# Generated by FakeRAM 2.0
VERSION 5.7 ;
BUSBITCHARS "[]" ;
PROPERTYDEFINITIONS
  MACRO width INTEGER ;
  MACRO depth INTEGER ;
  MACRO banks INTEGER ;
END PROPERTYDEFINITIONS
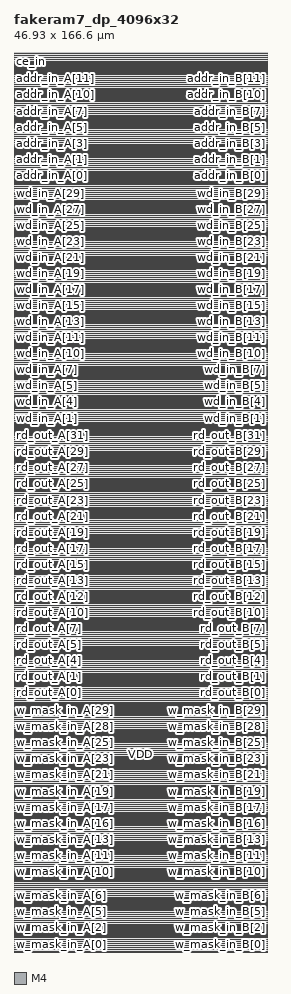
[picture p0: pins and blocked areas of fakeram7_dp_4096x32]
MACRO fakeram7_dp_4096x32
  PROPERTY width 32 ;
  PROPERTY depth 4096 ;
  PROPERTY banks 8 ;
  FOREIGN fakeram7_dp_4096x32 0 0 ;
  SYMMETRY X Y ;
  SIZE 46.930 BY 166.600 ;
  CLASS BLOCK ;
  PIN w_mask_in_A[0]
    DIRECTION INPUT ;
    USE SIGNAL ;
    SHAPE ABUTMENT ;
    PORT
      LAYER M4 ;
      RECT 0.000 0.048 0.024 0.072 ;
    END
  END w_mask_in_A[0]
  PIN w_mask_in_B[0]
    DIRECTION INPUT ;
    USE SIGNAL ;
    SHAPE ABUTMENT ;
    PORT
      LAYER M4 ;
      RECT 46.906 0.048 46.930 0.072 ;
    END
  END w_mask_in_B[0]
  PIN w_mask_in_A[1]
    DIRECTION INPUT ;
    USE SIGNAL ;
    SHAPE ABUTMENT ;
    PORT
      LAYER M4 ;
      RECT 0.000 1.536 0.024 1.560 ;
    END
  END w_mask_in_A[1]
  PIN w_mask_in_B[1]
    DIRECTION INPUT ;
    USE SIGNAL ;
    SHAPE ABUTMENT ;
    PORT
      LAYER M4 ;
      RECT 46.906 1.536 46.930 1.560 ;
    END
  END w_mask_in_B[1]
  PIN w_mask_in_A[2]
    DIRECTION INPUT ;
    USE SIGNAL ;
    SHAPE ABUTMENT ;
    PORT
      LAYER M4 ;
      RECT 0.000 3.024 0.024 3.048 ;
    END
  END w_mask_in_A[2]
  PIN w_mask_in_B[2]
    DIRECTION INPUT ;
    USE SIGNAL ;
    SHAPE ABUTMENT ;
    PORT
      LAYER M4 ;
      RECT 46.906 3.024 46.930 3.048 ;
    END
  END w_mask_in_B[2]
  PIN w_mask_in_A[3]
    DIRECTION INPUT ;
    USE SIGNAL ;
    SHAPE ABUTMENT ;
    PORT
      LAYER M4 ;
      RECT 0.000 4.512 0.024 4.536 ;
    END
  END w_mask_in_A[3]
  PIN w_mask_in_B[3]
    DIRECTION INPUT ;
    USE SIGNAL ;
    SHAPE ABUTMENT ;
    PORT
      LAYER M4 ;
      RECT 46.906 4.512 46.930 4.536 ;
    END
  END w_mask_in_B[3]
  PIN w_mask_in_A[4]
    DIRECTION INPUT ;
    USE SIGNAL ;
    SHAPE ABUTMENT ;
    PORT
      LAYER M4 ;
      RECT 0.000 6.000 0.024 6.024 ;
    END
  END w_mask_in_A[4]
  PIN w_mask_in_B[4]
    DIRECTION INPUT ;
    USE SIGNAL ;
    SHAPE ABUTMENT ;
    PORT
      LAYER M4 ;
      RECT 46.906 6.000 46.930 6.024 ;
    END
  END w_mask_in_B[4]
  PIN w_mask_in_A[5]
    DIRECTION INPUT ;
    USE SIGNAL ;
    SHAPE ABUTMENT ;
    PORT
      LAYER M4 ;
      RECT 0.000 7.488 0.024 7.512 ;
    END
  END w_mask_in_A[5]
  PIN w_mask_in_B[5]
    DIRECTION INPUT ;
    USE SIGNAL ;
    SHAPE ABUTMENT ;
    PORT
      LAYER M4 ;
      RECT 46.906 7.488 46.930 7.512 ;
    END
  END w_mask_in_B[5]
  PIN w_mask_in_A[6]
    DIRECTION INPUT ;
    USE SIGNAL ;
    SHAPE ABUTMENT ;
    PORT
      LAYER M4 ;
      RECT 0.000 8.976 0.024 9.000 ;
    END
  END w_mask_in_A[6]
  PIN w_mask_in_B[6]
    DIRECTION INPUT ;
    USE SIGNAL ;
    SHAPE ABUTMENT ;
    PORT
      LAYER M4 ;
      RECT 46.906 8.976 46.930 9.000 ;
    END
  END w_mask_in_B[6]
  PIN w_mask_in_A[7]
    DIRECTION INPUT ;
    USE SIGNAL ;
    SHAPE ABUTMENT ;
    PORT
      LAYER M4 ;
      RECT 0.000 10.464 0.024 10.488 ;
    END
  END w_mask_in_A[7]
  PIN w_mask_in_B[7]
    DIRECTION INPUT ;
    USE SIGNAL ;
    SHAPE ABUTMENT ;
    PORT
      LAYER M4 ;
      RECT 46.906 10.464 46.930 10.488 ;
    END
  END w_mask_in_B[7]
  PIN w_mask_in_A[8]
    DIRECTION INPUT ;
    USE SIGNAL ;
    SHAPE ABUTMENT ;
    PORT
      LAYER M4 ;
      RECT 0.000 11.952 0.024 11.976 ;
    END
  END w_mask_in_A[8]
  PIN w_mask_in_B[8]
    DIRECTION INPUT ;
    USE SIGNAL ;
    SHAPE ABUTMENT ;
    PORT
      LAYER M4 ;
      RECT 46.906 11.952 46.930 11.976 ;
    END
  END w_mask_in_B[8]
  PIN w_mask_in_A[9]
    DIRECTION INPUT ;
    USE SIGNAL ;
    SHAPE ABUTMENT ;
    PORT
      LAYER M4 ;
      RECT 0.000 13.440 0.024 13.464 ;
    END
  END w_mask_in_A[9]
  PIN w_mask_in_B[9]
    DIRECTION INPUT ;
    USE SIGNAL ;
    SHAPE ABUTMENT ;
    PORT
      LAYER M4 ;
      RECT 46.906 13.440 46.930 13.464 ;
    END
  END w_mask_in_B[9]
  PIN w_mask_in_A[10]
    DIRECTION INPUT ;
    USE SIGNAL ;
    SHAPE ABUTMENT ;
    PORT
      LAYER M4 ;
      RECT 0.000 14.928 0.024 14.952 ;
    END
  END w_mask_in_A[10]
  PIN w_mask_in_B[10]
    DIRECTION INPUT ;
    USE SIGNAL ;
    SHAPE ABUTMENT ;
    PORT
      LAYER M4 ;
      RECT 46.906 14.928 46.930 14.952 ;
    END
  END w_mask_in_B[10]
  PIN w_mask_in_A[11]
    DIRECTION INPUT ;
    USE SIGNAL ;
    SHAPE ABUTMENT ;
    PORT
      LAYER M4 ;
      RECT 0.000 16.416 0.024 16.440 ;
    END
  END w_mask_in_A[11]
  PIN w_mask_in_B[11]
    DIRECTION INPUT ;
    USE SIGNAL ;
    SHAPE ABUTMENT ;
    PORT
      LAYER M4 ;
      RECT 46.906 16.416 46.930 16.440 ;
    END
  END w_mask_in_B[11]
  PIN w_mask_in_A[12]
    DIRECTION INPUT ;
    USE SIGNAL ;
    SHAPE ABUTMENT ;
    PORT
      LAYER M4 ;
      RECT 0.000 17.904 0.024 17.928 ;
    END
  END w_mask_in_A[12]
  PIN w_mask_in_B[12]
    DIRECTION INPUT ;
    USE SIGNAL ;
    SHAPE ABUTMENT ;
    PORT
      LAYER M4 ;
      RECT 46.906 17.904 46.930 17.928 ;
    END
  END w_mask_in_B[12]
  PIN w_mask_in_A[13]
    DIRECTION INPUT ;
    USE SIGNAL ;
    SHAPE ABUTMENT ;
    PORT
      LAYER M4 ;
      RECT 0.000 19.392 0.024 19.416 ;
    END
  END w_mask_in_A[13]
  PIN w_mask_in_B[13]
    DIRECTION INPUT ;
    USE SIGNAL ;
    SHAPE ABUTMENT ;
    PORT
      LAYER M4 ;
      RECT 46.906 19.392 46.930 19.416 ;
    END
  END w_mask_in_B[13]
  PIN w_mask_in_A[14]
    DIRECTION INPUT ;
    USE SIGNAL ;
    SHAPE ABUTMENT ;
    PORT
      LAYER M4 ;
      RECT 0.000 20.880 0.024 20.904 ;
    END
  END w_mask_in_A[14]
  PIN w_mask_in_B[14]
    DIRECTION INPUT ;
    USE SIGNAL ;
    SHAPE ABUTMENT ;
    PORT
      LAYER M4 ;
      RECT 46.906 20.880 46.930 20.904 ;
    END
  END w_mask_in_B[14]
  PIN w_mask_in_A[15]
    DIRECTION INPUT ;
    USE SIGNAL ;
    SHAPE ABUTMENT ;
    PORT
      LAYER M4 ;
      RECT 0.000 22.368 0.024 22.392 ;
    END
  END w_mask_in_A[15]
  PIN w_mask_in_B[15]
    DIRECTION INPUT ;
    USE SIGNAL ;
    SHAPE ABUTMENT ;
    PORT
      LAYER M4 ;
      RECT 46.906 22.368 46.930 22.392 ;
    END
  END w_mask_in_B[15]
  PIN w_mask_in_A[16]
    DIRECTION INPUT ;
    USE SIGNAL ;
    SHAPE ABUTMENT ;
    PORT
      LAYER M4 ;
      RECT 0.000 23.856 0.024 23.880 ;
    END
  END w_mask_in_A[16]
  PIN w_mask_in_B[16]
    DIRECTION INPUT ;
    USE SIGNAL ;
    SHAPE ABUTMENT ;
    PORT
      LAYER M4 ;
      RECT 46.906 23.856 46.930 23.880 ;
    END
  END w_mask_in_B[16]
  PIN w_mask_in_A[17]
    DIRECTION INPUT ;
    USE SIGNAL ;
    SHAPE ABUTMENT ;
    PORT
      LAYER M4 ;
      RECT 0.000 25.344 0.024 25.368 ;
    END
  END w_mask_in_A[17]
  PIN w_mask_in_B[17]
    DIRECTION INPUT ;
    USE SIGNAL ;
    SHAPE ABUTMENT ;
    PORT
      LAYER M4 ;
      RECT 46.906 25.344 46.930 25.368 ;
    END
  END w_mask_in_B[17]
  PIN w_mask_in_A[18]
    DIRECTION INPUT ;
    USE SIGNAL ;
    SHAPE ABUTMENT ;
    PORT
      LAYER M4 ;
      RECT 0.000 26.832 0.024 26.856 ;
    END
  END w_mask_in_A[18]
  PIN w_mask_in_B[18]
    DIRECTION INPUT ;
    USE SIGNAL ;
    SHAPE ABUTMENT ;
    PORT
      LAYER M4 ;
      RECT 46.906 26.832 46.930 26.856 ;
    END
  END w_mask_in_B[18]
  PIN w_mask_in_A[19]
    DIRECTION INPUT ;
    USE SIGNAL ;
    SHAPE ABUTMENT ;
    PORT
      LAYER M4 ;
      RECT 0.000 28.320 0.024 28.344 ;
    END
  END w_mask_in_A[19]
  PIN w_mask_in_B[19]
    DIRECTION INPUT ;
    USE SIGNAL ;
    SHAPE ABUTMENT ;
    PORT
      LAYER M4 ;
      RECT 46.906 28.320 46.930 28.344 ;
    END
  END w_mask_in_B[19]
  PIN w_mask_in_A[20]
    DIRECTION INPUT ;
    USE SIGNAL ;
    SHAPE ABUTMENT ;
    PORT
      LAYER M4 ;
      RECT 0.000 29.808 0.024 29.832 ;
    END
  END w_mask_in_A[20]
  PIN w_mask_in_B[20]
    DIRECTION INPUT ;
    USE SIGNAL ;
    SHAPE ABUTMENT ;
    PORT
      LAYER M4 ;
      RECT 46.906 29.808 46.930 29.832 ;
    END
  END w_mask_in_B[20]
  PIN w_mask_in_A[21]
    DIRECTION INPUT ;
    USE SIGNAL ;
    SHAPE ABUTMENT ;
    PORT
      LAYER M4 ;
      RECT 0.000 31.296 0.024 31.320 ;
    END
  END w_mask_in_A[21]
  PIN w_mask_in_B[21]
    DIRECTION INPUT ;
    USE SIGNAL ;
    SHAPE ABUTMENT ;
    PORT
      LAYER M4 ;
      RECT 46.906 31.296 46.930 31.320 ;
    END
  END w_mask_in_B[21]
  PIN w_mask_in_A[22]
    DIRECTION INPUT ;
    USE SIGNAL ;
    SHAPE ABUTMENT ;
    PORT
      LAYER M4 ;
      RECT 0.000 32.784 0.024 32.808 ;
    END
  END w_mask_in_A[22]
  PIN w_mask_in_B[22]
    DIRECTION INPUT ;
    USE SIGNAL ;
    SHAPE ABUTMENT ;
    PORT
      LAYER M4 ;
      RECT 46.906 32.784 46.930 32.808 ;
    END
  END w_mask_in_B[22]
  PIN w_mask_in_A[23]
    DIRECTION INPUT ;
    USE SIGNAL ;
    SHAPE ABUTMENT ;
    PORT
      LAYER M4 ;
      RECT 0.000 34.272 0.024 34.296 ;
    END
  END w_mask_in_A[23]
  PIN w_mask_in_B[23]
    DIRECTION INPUT ;
    USE SIGNAL ;
    SHAPE ABUTMENT ;
    PORT
      LAYER M4 ;
      RECT 46.906 34.272 46.930 34.296 ;
    END
  END w_mask_in_B[23]
  PIN w_mask_in_A[24]
    DIRECTION INPUT ;
    USE SIGNAL ;
    SHAPE ABUTMENT ;
    PORT
      LAYER M4 ;
      RECT 0.000 35.760 0.024 35.784 ;
    END
  END w_mask_in_A[24]
  PIN w_mask_in_B[24]
    DIRECTION INPUT ;
    USE SIGNAL ;
    SHAPE ABUTMENT ;
    PORT
      LAYER M4 ;
      RECT 46.906 35.760 46.930 35.784 ;
    END
  END w_mask_in_B[24]
  PIN w_mask_in_A[25]
    DIRECTION INPUT ;
    USE SIGNAL ;
    SHAPE ABUTMENT ;
    PORT
      LAYER M4 ;
      RECT 0.000 37.248 0.024 37.272 ;
    END
  END w_mask_in_A[25]
  PIN w_mask_in_B[25]
    DIRECTION INPUT ;
    USE SIGNAL ;
    SHAPE ABUTMENT ;
    PORT
      LAYER M4 ;
      RECT 46.906 37.248 46.930 37.272 ;
    END
  END w_mask_in_B[25]
  PIN w_mask_in_A[26]
    DIRECTION INPUT ;
    USE SIGNAL ;
    SHAPE ABUTMENT ;
    PORT
      LAYER M4 ;
      RECT 0.000 38.736 0.024 38.760 ;
    END
  END w_mask_in_A[26]
  PIN w_mask_in_B[26]
    DIRECTION INPUT ;
    USE SIGNAL ;
    SHAPE ABUTMENT ;
    PORT
      LAYER M4 ;
      RECT 46.906 38.736 46.930 38.760 ;
    END
  END w_mask_in_B[26]
  PIN w_mask_in_A[27]
    DIRECTION INPUT ;
    USE SIGNAL ;
    SHAPE ABUTMENT ;
    PORT
      LAYER M4 ;
      RECT 0.000 40.224 0.024 40.248 ;
    END
  END w_mask_in_A[27]
  PIN w_mask_in_B[27]
    DIRECTION INPUT ;
    USE SIGNAL ;
    SHAPE ABUTMENT ;
    PORT
      LAYER M4 ;
      RECT 46.906 40.224 46.930 40.248 ;
    END
  END w_mask_in_B[27]
  PIN w_mask_in_A[28]
    DIRECTION INPUT ;
    USE SIGNAL ;
    SHAPE ABUTMENT ;
    PORT
      LAYER M4 ;
      RECT 0.000 41.712 0.024 41.736 ;
    END
  END w_mask_in_A[28]
  PIN w_mask_in_B[28]
    DIRECTION INPUT ;
    USE SIGNAL ;
    SHAPE ABUTMENT ;
    PORT
      LAYER M4 ;
      RECT 46.906 41.712 46.930 41.736 ;
    END
  END w_mask_in_B[28]
  PIN w_mask_in_A[29]
    DIRECTION INPUT ;
    USE SIGNAL ;
    SHAPE ABUTMENT ;
    PORT
      LAYER M4 ;
      RECT 0.000 43.200 0.024 43.224 ;
    END
  END w_mask_in_A[29]
  PIN w_mask_in_B[29]
    DIRECTION INPUT ;
    USE SIGNAL ;
    SHAPE ABUTMENT ;
    PORT
      LAYER M4 ;
      RECT 46.906 43.200 46.930 43.224 ;
    END
  END w_mask_in_B[29]
  PIN w_mask_in_A[30]
    DIRECTION INPUT ;
    USE SIGNAL ;
    SHAPE ABUTMENT ;
    PORT
      LAYER M4 ;
      RECT 0.000 44.688 0.024 44.712 ;
    END
  END w_mask_in_A[30]
  PIN w_mask_in_B[30]
    DIRECTION INPUT ;
    USE SIGNAL ;
    SHAPE ABUTMENT ;
    PORT
      LAYER M4 ;
      RECT 46.906 44.688 46.930 44.712 ;
    END
  END w_mask_in_B[30]
  PIN w_mask_in_A[31]
    DIRECTION INPUT ;
    USE SIGNAL ;
    SHAPE ABUTMENT ;
    PORT
      LAYER M4 ;
      RECT 0.000 46.176 0.024 46.200 ;
    END
  END w_mask_in_A[31]
  PIN w_mask_in_B[31]
    DIRECTION INPUT ;
    USE SIGNAL ;
    SHAPE ABUTMENT ;
    PORT
      LAYER M4 ;
      RECT 46.906 46.176 46.930 46.200 ;
    END
  END w_mask_in_B[31]
  PIN rd_out_A[0]
    DIRECTION OUTPUT ;
    USE SIGNAL ;
    SHAPE ABUTMENT ;
    PORT
      LAYER M4 ;
      RECT 0.000 47.952 0.024 47.976 ;
    END
  END rd_out_A[0]
  PIN rd_out_B[0]
    DIRECTION OUTPUT ;
    USE SIGNAL ;
    SHAPE ABUTMENT ;
    PORT
      LAYER M4 ;
      RECT 46.906 47.952 46.930 47.976 ;
    END
  END rd_out_B[0]
  PIN rd_out_A[1]
    DIRECTION OUTPUT ;
    USE SIGNAL ;
    SHAPE ABUTMENT ;
    PORT
      LAYER M4 ;
      RECT 0.000 49.440 0.024 49.464 ;
    END
  END rd_out_A[1]
  PIN rd_out_B[1]
    DIRECTION OUTPUT ;
    USE SIGNAL ;
    SHAPE ABUTMENT ;
    PORT
      LAYER M4 ;
      RECT 46.906 49.440 46.930 49.464 ;
    END
  END rd_out_B[1]
  PIN rd_out_A[2]
    DIRECTION OUTPUT ;
    USE SIGNAL ;
    SHAPE ABUTMENT ;
    PORT
      LAYER M4 ;
      RECT 0.000 50.928 0.024 50.952 ;
    END
  END rd_out_A[2]
  PIN rd_out_B[2]
    DIRECTION OUTPUT ;
    USE SIGNAL ;
    SHAPE ABUTMENT ;
    PORT
      LAYER M4 ;
      RECT 46.906 50.928 46.930 50.952 ;
    END
  END rd_out_B[2]
  PIN rd_out_A[3]
    DIRECTION OUTPUT ;
    USE SIGNAL ;
    SHAPE ABUTMENT ;
    PORT
      LAYER M4 ;
      RECT 0.000 52.416 0.024 52.440 ;
    END
  END rd_out_A[3]
  PIN rd_out_B[3]
    DIRECTION OUTPUT ;
    USE SIGNAL ;
    SHAPE ABUTMENT ;
    PORT
      LAYER M4 ;
      RECT 46.906 52.416 46.930 52.440 ;
    END
  END rd_out_B[3]
  PIN rd_out_A[4]
    DIRECTION OUTPUT ;
    USE SIGNAL ;
    SHAPE ABUTMENT ;
    PORT
      LAYER M4 ;
      RECT 0.000 53.904 0.024 53.928 ;
    END
  END rd_out_A[4]
  PIN rd_out_B[4]
    DIRECTION OUTPUT ;
    USE SIGNAL ;
    SHAPE ABUTMENT ;
    PORT
      LAYER M4 ;
      RECT 46.906 53.904 46.930 53.928 ;
    END
  END rd_out_B[4]
  PIN rd_out_A[5]
    DIRECTION OUTPUT ;
    USE SIGNAL ;
    SHAPE ABUTMENT ;
    PORT
      LAYER M4 ;
      RECT 0.000 55.392 0.024 55.416 ;
    END
  END rd_out_A[5]
  PIN rd_out_B[5]
    DIRECTION OUTPUT ;
    USE SIGNAL ;
    SHAPE ABUTMENT ;
    PORT
      LAYER M4 ;
      RECT 46.906 55.392 46.930 55.416 ;
    END
  END rd_out_B[5]
  PIN rd_out_A[6]
    DIRECTION OUTPUT ;
    USE SIGNAL ;
    SHAPE ABUTMENT ;
    PORT
      LAYER M4 ;
      RECT 0.000 56.880 0.024 56.904 ;
    END
  END rd_out_A[6]
  PIN rd_out_B[6]
    DIRECTION OUTPUT ;
    USE SIGNAL ;
    SHAPE ABUTMENT ;
    PORT
      LAYER M4 ;
      RECT 46.906 56.880 46.930 56.904 ;
    END
  END rd_out_B[6]
  PIN rd_out_A[7]
    DIRECTION OUTPUT ;
    USE SIGNAL ;
    SHAPE ABUTMENT ;
    PORT
      LAYER M4 ;
      RECT 0.000 58.368 0.024 58.392 ;
    END
  END rd_out_A[7]
  PIN rd_out_B[7]
    DIRECTION OUTPUT ;
    USE SIGNAL ;
    SHAPE ABUTMENT ;
    PORT
      LAYER M4 ;
      RECT 46.906 58.368 46.930 58.392 ;
    END
  END rd_out_B[7]
  PIN rd_out_A[8]
    DIRECTION OUTPUT ;
    USE SIGNAL ;
    SHAPE ABUTMENT ;
    PORT
      LAYER M4 ;
      RECT 0.000 59.856 0.024 59.880 ;
    END
  END rd_out_A[8]
  PIN rd_out_B[8]
    DIRECTION OUTPUT ;
    USE SIGNAL ;
    SHAPE ABUTMENT ;
    PORT
      LAYER M4 ;
      RECT 46.906 59.856 46.930 59.880 ;
    END
  END rd_out_B[8]
  PIN rd_out_A[9]
    DIRECTION OUTPUT ;
    USE SIGNAL ;
    SHAPE ABUTMENT ;
    PORT
      LAYER M4 ;
      RECT 0.000 61.344 0.024 61.368 ;
    END
  END rd_out_A[9]
  PIN rd_out_B[9]
    DIRECTION OUTPUT ;
    USE SIGNAL ;
    SHAPE ABUTMENT ;
    PORT
      LAYER M4 ;
      RECT 46.906 61.344 46.930 61.368 ;
    END
  END rd_out_B[9]
  PIN rd_out_A[10]
    DIRECTION OUTPUT ;
    USE SIGNAL ;
    SHAPE ABUTMENT ;
    PORT
      LAYER M4 ;
      RECT 0.000 62.832 0.024 62.856 ;
    END
  END rd_out_A[10]
  PIN rd_out_B[10]
    DIRECTION OUTPUT ;
    USE SIGNAL ;
    SHAPE ABUTMENT ;
    PORT
      LAYER M4 ;
      RECT 46.906 62.832 46.930 62.856 ;
    END
  END rd_out_B[10]
  PIN rd_out_A[11]
    DIRECTION OUTPUT ;
    USE SIGNAL ;
    SHAPE ABUTMENT ;
    PORT
      LAYER M4 ;
      RECT 0.000 64.320 0.024 64.344 ;
    END
  END rd_out_A[11]
  PIN rd_out_B[11]
    DIRECTION OUTPUT ;
    USE SIGNAL ;
    SHAPE ABUTMENT ;
    PORT
      LAYER M4 ;
      RECT 46.906 64.320 46.930 64.344 ;
    END
  END rd_out_B[11]
  PIN rd_out_A[12]
    DIRECTION OUTPUT ;
    USE SIGNAL ;
    SHAPE ABUTMENT ;
    PORT
      LAYER M4 ;
      RECT 0.000 65.808 0.024 65.832 ;
    END
  END rd_out_A[12]
  PIN rd_out_B[12]
    DIRECTION OUTPUT ;
    USE SIGNAL ;
    SHAPE ABUTMENT ;
    PORT
      LAYER M4 ;
      RECT 46.906 65.808 46.930 65.832 ;
    END
  END rd_out_B[12]
  PIN rd_out_A[13]
    DIRECTION OUTPUT ;
    USE SIGNAL ;
    SHAPE ABUTMENT ;
    PORT
      LAYER M4 ;
      RECT 0.000 67.296 0.024 67.320 ;
    END
  END rd_out_A[13]
  PIN rd_out_B[13]
    DIRECTION OUTPUT ;
    USE SIGNAL ;
    SHAPE ABUTMENT ;
    PORT
      LAYER M4 ;
      RECT 46.906 67.296 46.930 67.320 ;
    END
  END rd_out_B[13]
  PIN rd_out_A[14]
    DIRECTION OUTPUT ;
    USE SIGNAL ;
    SHAPE ABUTMENT ;
    PORT
      LAYER M4 ;
      RECT 0.000 68.784 0.024 68.808 ;
    END
  END rd_out_A[14]
  PIN rd_out_B[14]
    DIRECTION OUTPUT ;
    USE SIGNAL ;
    SHAPE ABUTMENT ;
    PORT
      LAYER M4 ;
      RECT 46.906 68.784 46.930 68.808 ;
    END
  END rd_out_B[14]
  PIN rd_out_A[15]
    DIRECTION OUTPUT ;
    USE SIGNAL ;
    SHAPE ABUTMENT ;
    PORT
      LAYER M4 ;
      RECT 0.000 70.272 0.024 70.296 ;
    END
  END rd_out_A[15]
  PIN rd_out_B[15]
    DIRECTION OUTPUT ;
    USE SIGNAL ;
    SHAPE ABUTMENT ;
    PORT
      LAYER M4 ;
      RECT 46.906 70.272 46.930 70.296 ;
    END
  END rd_out_B[15]
  PIN rd_out_A[16]
    DIRECTION OUTPUT ;
    USE SIGNAL ;
    SHAPE ABUTMENT ;
    PORT
      LAYER M4 ;
      RECT 0.000 71.760 0.024 71.784 ;
    END
  END rd_out_A[16]
  PIN rd_out_B[16]
    DIRECTION OUTPUT ;
    USE SIGNAL ;
    SHAPE ABUTMENT ;
    PORT
      LAYER M4 ;
      RECT 46.906 71.760 46.930 71.784 ;
    END
  END rd_out_B[16]
  PIN rd_out_A[17]
    DIRECTION OUTPUT ;
    USE SIGNAL ;
    SHAPE ABUTMENT ;
    PORT
      LAYER M4 ;
      RECT 0.000 73.248 0.024 73.272 ;
    END
  END rd_out_A[17]
  PIN rd_out_B[17]
    DIRECTION OUTPUT ;
    USE SIGNAL ;
    SHAPE ABUTMENT ;
    PORT
      LAYER M4 ;
      RECT 46.906 73.248 46.930 73.272 ;
    END
  END rd_out_B[17]
  PIN rd_out_A[18]
    DIRECTION OUTPUT ;
    USE SIGNAL ;
    SHAPE ABUTMENT ;
    PORT
      LAYER M4 ;
      RECT 0.000 74.736 0.024 74.760 ;
    END
  END rd_out_A[18]
  PIN rd_out_B[18]
    DIRECTION OUTPUT ;
    USE SIGNAL ;
    SHAPE ABUTMENT ;
    PORT
      LAYER M4 ;
      RECT 46.906 74.736 46.930 74.760 ;
    END
  END rd_out_B[18]
  PIN rd_out_A[19]
    DIRECTION OUTPUT ;
    USE SIGNAL ;
    SHAPE ABUTMENT ;
    PORT
      LAYER M4 ;
      RECT 0.000 76.224 0.024 76.248 ;
    END
  END rd_out_A[19]
  PIN rd_out_B[19]
    DIRECTION OUTPUT ;
    USE SIGNAL ;
    SHAPE ABUTMENT ;
    PORT
      LAYER M4 ;
      RECT 46.906 76.224 46.930 76.248 ;
    END
  END rd_out_B[19]
  PIN rd_out_A[20]
    DIRECTION OUTPUT ;
    USE SIGNAL ;
    SHAPE ABUTMENT ;
    PORT
      LAYER M4 ;
      RECT 0.000 77.712 0.024 77.736 ;
    END
  END rd_out_A[20]
  PIN rd_out_B[20]
    DIRECTION OUTPUT ;
    USE SIGNAL ;
    SHAPE ABUTMENT ;
    PORT
      LAYER M4 ;
      RECT 46.906 77.712 46.930 77.736 ;
    END
  END rd_out_B[20]
  PIN rd_out_A[21]
    DIRECTION OUTPUT ;
    USE SIGNAL ;
    SHAPE ABUTMENT ;
    PORT
      LAYER M4 ;
      RECT 0.000 79.200 0.024 79.224 ;
    END
  END rd_out_A[21]
  PIN rd_out_B[21]
    DIRECTION OUTPUT ;
    USE SIGNAL ;
    SHAPE ABUTMENT ;
    PORT
      LAYER M4 ;
      RECT 46.906 79.200 46.930 79.224 ;
    END
  END rd_out_B[21]
  PIN rd_out_A[22]
    DIRECTION OUTPUT ;
    USE SIGNAL ;
    SHAPE ABUTMENT ;
    PORT
      LAYER M4 ;
      RECT 0.000 80.688 0.024 80.712 ;
    END
  END rd_out_A[22]
  PIN rd_out_B[22]
    DIRECTION OUTPUT ;
    USE SIGNAL ;
    SHAPE ABUTMENT ;
    PORT
      LAYER M4 ;
      RECT 46.906 80.688 46.930 80.712 ;
    END
  END rd_out_B[22]
  PIN rd_out_A[23]
    DIRECTION OUTPUT ;
    USE SIGNAL ;
    SHAPE ABUTMENT ;
    PORT
      LAYER M4 ;
      RECT 0.000 82.176 0.024 82.200 ;
    END
  END rd_out_A[23]
  PIN rd_out_B[23]
    DIRECTION OUTPUT ;
    USE SIGNAL ;
    SHAPE ABUTMENT ;
    PORT
      LAYER M4 ;
      RECT 46.906 82.176 46.930 82.200 ;
    END
  END rd_out_B[23]
  PIN rd_out_A[24]
    DIRECTION OUTPUT ;
    USE SIGNAL ;
    SHAPE ABUTMENT ;
    PORT
      LAYER M4 ;
      RECT 0.000 83.664 0.024 83.688 ;
    END
  END rd_out_A[24]
  PIN rd_out_B[24]
    DIRECTION OUTPUT ;
    USE SIGNAL ;
    SHAPE ABUTMENT ;
    PORT
      LAYER M4 ;
      RECT 46.906 83.664 46.930 83.688 ;
    END
  END rd_out_B[24]
  PIN rd_out_A[25]
    DIRECTION OUTPUT ;
    USE SIGNAL ;
    SHAPE ABUTMENT ;
    PORT
      LAYER M4 ;
      RECT 0.000 85.152 0.024 85.176 ;
    END
  END rd_out_A[25]
  PIN rd_out_B[25]
    DIRECTION OUTPUT ;
    USE SIGNAL ;
    SHAPE ABUTMENT ;
    PORT
      LAYER M4 ;
      RECT 46.906 85.152 46.930 85.176 ;
    END
  END rd_out_B[25]
  PIN rd_out_A[26]
    DIRECTION OUTPUT ;
    USE SIGNAL ;
    SHAPE ABUTMENT ;
    PORT
      LAYER M4 ;
      RECT 0.000 86.640 0.024 86.664 ;
    END
  END rd_out_A[26]
  PIN rd_out_B[26]
    DIRECTION OUTPUT ;
    USE SIGNAL ;
    SHAPE ABUTMENT ;
    PORT
      LAYER M4 ;
      RECT 46.906 86.640 46.930 86.664 ;
    END
  END rd_out_B[26]
  PIN rd_out_A[27]
    DIRECTION OUTPUT ;
    USE SIGNAL ;
    SHAPE ABUTMENT ;
    PORT
      LAYER M4 ;
      RECT 0.000 88.128 0.024 88.152 ;
    END
  END rd_out_A[27]
  PIN rd_out_B[27]
    DIRECTION OUTPUT ;
    USE SIGNAL ;
    SHAPE ABUTMENT ;
    PORT
      LAYER M4 ;
      RECT 46.906 88.128 46.930 88.152 ;
    END
  END rd_out_B[27]
  PIN rd_out_A[28]
    DIRECTION OUTPUT ;
    USE SIGNAL ;
    SHAPE ABUTMENT ;
    PORT
      LAYER M4 ;
      RECT 0.000 89.616 0.024 89.640 ;
    END
  END rd_out_A[28]
  PIN rd_out_B[28]
    DIRECTION OUTPUT ;
    USE SIGNAL ;
    SHAPE ABUTMENT ;
    PORT
      LAYER M4 ;
      RECT 46.906 89.616 46.930 89.640 ;
    END
  END rd_out_B[28]
  PIN rd_out_A[29]
    DIRECTION OUTPUT ;
    USE SIGNAL ;
    SHAPE ABUTMENT ;
    PORT
      LAYER M4 ;
      RECT 0.000 91.104 0.024 91.128 ;
    END
  END rd_out_A[29]
  PIN rd_out_B[29]
    DIRECTION OUTPUT ;
    USE SIGNAL ;
    SHAPE ABUTMENT ;
    PORT
      LAYER M4 ;
      RECT 46.906 91.104 46.930 91.128 ;
    END
  END rd_out_B[29]
  PIN rd_out_A[30]
    DIRECTION OUTPUT ;
    USE SIGNAL ;
    SHAPE ABUTMENT ;
    PORT
      LAYER M4 ;
      RECT 0.000 92.592 0.024 92.616 ;
    END
  END rd_out_A[30]
  PIN rd_out_B[30]
    DIRECTION OUTPUT ;
    USE SIGNAL ;
    SHAPE ABUTMENT ;
    PORT
      LAYER M4 ;
      RECT 46.906 92.592 46.930 92.616 ;
    END
  END rd_out_B[30]
  PIN rd_out_A[31]
    DIRECTION OUTPUT ;
    USE SIGNAL ;
    SHAPE ABUTMENT ;
    PORT
      LAYER M4 ;
      RECT 0.000 94.080 0.024 94.104 ;
    END
  END rd_out_A[31]
  PIN rd_out_B[31]
    DIRECTION OUTPUT ;
    USE SIGNAL ;
    SHAPE ABUTMENT ;
    PORT
      LAYER M4 ;
      RECT 46.906 94.080 46.930 94.104 ;
    END
  END rd_out_B[31]
  PIN wd_in_A[0]
    DIRECTION INPUT ;
    USE SIGNAL ;
    SHAPE ABUTMENT ;
    PORT
      LAYER M4 ;
      RECT 0.000 95.856 0.024 95.880 ;
    END
  END wd_in_A[0]
  PIN wd_in_B[0]
    DIRECTION INPUT ;
    USE SIGNAL ;
    SHAPE ABUTMENT ;
    PORT
      LAYER M4 ;
      RECT 46.906 95.856 46.930 95.880 ;
    END
  END wd_in_B[0]
  PIN wd_in_A[1]
    DIRECTION INPUT ;
    USE SIGNAL ;
    SHAPE ABUTMENT ;
    PORT
      LAYER M4 ;
      RECT 0.000 97.344 0.024 97.368 ;
    END
  END wd_in_A[1]
  PIN wd_in_B[1]
    DIRECTION INPUT ;
    USE SIGNAL ;
    SHAPE ABUTMENT ;
    PORT
      LAYER M4 ;
      RECT 46.906 97.344 46.930 97.368 ;
    END
  END wd_in_B[1]
  PIN wd_in_A[2]
    DIRECTION INPUT ;
    USE SIGNAL ;
    SHAPE ABUTMENT ;
    PORT
      LAYER M4 ;
      RECT 0.000 98.832 0.024 98.856 ;
    END
  END wd_in_A[2]
  PIN wd_in_B[2]
    DIRECTION INPUT ;
    USE SIGNAL ;
    SHAPE ABUTMENT ;
    PORT
      LAYER M4 ;
      RECT 46.906 98.832 46.930 98.856 ;
    END
  END wd_in_B[2]
  PIN wd_in_A[3]
    DIRECTION INPUT ;
    USE SIGNAL ;
    SHAPE ABUTMENT ;
    PORT
      LAYER M4 ;
      RECT 0.000 100.320 0.024 100.344 ;
    END
  END wd_in_A[3]
  PIN wd_in_B[3]
    DIRECTION INPUT ;
    USE SIGNAL ;
    SHAPE ABUTMENT ;
    PORT
      LAYER M4 ;
      RECT 46.906 100.320 46.930 100.344 ;
    END
  END wd_in_B[3]
  PIN wd_in_A[4]
    DIRECTION INPUT ;
    USE SIGNAL ;
    SHAPE ABUTMENT ;
    PORT
      LAYER M4 ;
      RECT 0.000 101.808 0.024 101.832 ;
    END
  END wd_in_A[4]
  PIN wd_in_B[4]
    DIRECTION INPUT ;
    USE SIGNAL ;
    SHAPE ABUTMENT ;
    PORT
      LAYER M4 ;
      RECT 46.906 101.808 46.930 101.832 ;
    END
  END wd_in_B[4]
  PIN wd_in_A[5]
    DIRECTION INPUT ;
    USE SIGNAL ;
    SHAPE ABUTMENT ;
    PORT
      LAYER M4 ;
      RECT 0.000 103.296 0.024 103.320 ;
    END
  END wd_in_A[5]
  PIN wd_in_B[5]
    DIRECTION INPUT ;
    USE SIGNAL ;
    SHAPE ABUTMENT ;
    PORT
      LAYER M4 ;
      RECT 46.906 103.296 46.930 103.320 ;
    END
  END wd_in_B[5]
  PIN wd_in_A[6]
    DIRECTION INPUT ;
    USE SIGNAL ;
    SHAPE ABUTMENT ;
    PORT
      LAYER M4 ;
      RECT 0.000 104.784 0.024 104.808 ;
    END
  END wd_in_A[6]
  PIN wd_in_B[6]
    DIRECTION INPUT ;
    USE SIGNAL ;
    SHAPE ABUTMENT ;
    PORT
      LAYER M4 ;
      RECT 46.906 104.784 46.930 104.808 ;
    END
  END wd_in_B[6]
  PIN wd_in_A[7]
    DIRECTION INPUT ;
    USE SIGNAL ;
    SHAPE ABUTMENT ;
    PORT
      LAYER M4 ;
      RECT 0.000 106.272 0.024 106.296 ;
    END
  END wd_in_A[7]
  PIN wd_in_B[7]
    DIRECTION INPUT ;
    USE SIGNAL ;
    SHAPE ABUTMENT ;
    PORT
      LAYER M4 ;
      RECT 46.906 106.272 46.930 106.296 ;
    END
  END wd_in_B[7]
  PIN wd_in_A[8]
    DIRECTION INPUT ;
    USE SIGNAL ;
    SHAPE ABUTMENT ;
    PORT
      LAYER M4 ;
      RECT 0.000 107.760 0.024 107.784 ;
    END
  END wd_in_A[8]
  PIN wd_in_B[8]
    DIRECTION INPUT ;
    USE SIGNAL ;
    SHAPE ABUTMENT ;
    PORT
      LAYER M4 ;
      RECT 46.906 107.760 46.930 107.784 ;
    END
  END wd_in_B[8]
  PIN wd_in_A[9]
    DIRECTION INPUT ;
    USE SIGNAL ;
    SHAPE ABUTMENT ;
    PORT
      LAYER M4 ;
      RECT 0.000 109.248 0.024 109.272 ;
    END
  END wd_in_A[9]
  PIN wd_in_B[9]
    DIRECTION INPUT ;
    USE SIGNAL ;
    SHAPE ABUTMENT ;
    PORT
      LAYER M4 ;
      RECT 46.906 109.248 46.930 109.272 ;
    END
  END wd_in_B[9]
  PIN wd_in_A[10]
    DIRECTION INPUT ;
    USE SIGNAL ;
    SHAPE ABUTMENT ;
    PORT
      LAYER M4 ;
      RECT 0.000 110.736 0.024 110.760 ;
    END
  END wd_in_A[10]
  PIN wd_in_B[10]
    DIRECTION INPUT ;
    USE SIGNAL ;
    SHAPE ABUTMENT ;
    PORT
      LAYER M4 ;
      RECT 46.906 110.736 46.930 110.760 ;
    END
  END wd_in_B[10]
  PIN wd_in_A[11]
    DIRECTION INPUT ;
    USE SIGNAL ;
    SHAPE ABUTMENT ;
    PORT
      LAYER M4 ;
      RECT 0.000 112.224 0.024 112.248 ;
    END
  END wd_in_A[11]
  PIN wd_in_B[11]
    DIRECTION INPUT ;
    USE SIGNAL ;
    SHAPE ABUTMENT ;
    PORT
      LAYER M4 ;
      RECT 46.906 112.224 46.930 112.248 ;
    END
  END wd_in_B[11]
  PIN wd_in_A[12]
    DIRECTION INPUT ;
    USE SIGNAL ;
    SHAPE ABUTMENT ;
    PORT
      LAYER M4 ;
      RECT 0.000 113.712 0.024 113.736 ;
    END
  END wd_in_A[12]
  PIN wd_in_B[12]
    DIRECTION INPUT ;
    USE SIGNAL ;
    SHAPE ABUTMENT ;
    PORT
      LAYER M4 ;
      RECT 46.906 113.712 46.930 113.736 ;
    END
  END wd_in_B[12]
  PIN wd_in_A[13]
    DIRECTION INPUT ;
    USE SIGNAL ;
    SHAPE ABUTMENT ;
    PORT
      LAYER M4 ;
      RECT 0.000 115.200 0.024 115.224 ;
    END
  END wd_in_A[13]
  PIN wd_in_B[13]
    DIRECTION INPUT ;
    USE SIGNAL ;
    SHAPE ABUTMENT ;
    PORT
      LAYER M4 ;
      RECT 46.906 115.200 46.930 115.224 ;
    END
  END wd_in_B[13]
  PIN wd_in_A[14]
    DIRECTION INPUT ;
    USE SIGNAL ;
    SHAPE ABUTMENT ;
    PORT
      LAYER M4 ;
      RECT 0.000 116.688 0.024 116.712 ;
    END
  END wd_in_A[14]
  PIN wd_in_B[14]
    DIRECTION INPUT ;
    USE SIGNAL ;
    SHAPE ABUTMENT ;
    PORT
      LAYER M4 ;
      RECT 46.906 116.688 46.930 116.712 ;
    END
  END wd_in_B[14]
  PIN wd_in_A[15]
    DIRECTION INPUT ;
    USE SIGNAL ;
    SHAPE ABUTMENT ;
    PORT
      LAYER M4 ;
      RECT 0.000 118.176 0.024 118.200 ;
    END
  END wd_in_A[15]
  PIN wd_in_B[15]
    DIRECTION INPUT ;
    USE SIGNAL ;
    SHAPE ABUTMENT ;
    PORT
      LAYER M4 ;
      RECT 46.906 118.176 46.930 118.200 ;
    END
  END wd_in_B[15]
  PIN wd_in_A[16]
    DIRECTION INPUT ;
    USE SIGNAL ;
    SHAPE ABUTMENT ;
    PORT
      LAYER M4 ;
      RECT 0.000 119.664 0.024 119.688 ;
    END
  END wd_in_A[16]
  PIN wd_in_B[16]
    DIRECTION INPUT ;
    USE SIGNAL ;
    SHAPE ABUTMENT ;
    PORT
      LAYER M4 ;
      RECT 46.906 119.664 46.930 119.688 ;
    END
  END wd_in_B[16]
  PIN wd_in_A[17]
    DIRECTION INPUT ;
    USE SIGNAL ;
    SHAPE ABUTMENT ;
    PORT
      LAYER M4 ;
      RECT 0.000 121.152 0.024 121.176 ;
    END
  END wd_in_A[17]
  PIN wd_in_B[17]
    DIRECTION INPUT ;
    USE SIGNAL ;
    SHAPE ABUTMENT ;
    PORT
      LAYER M4 ;
      RECT 46.906 121.152 46.930 121.176 ;
    END
  END wd_in_B[17]
  PIN wd_in_A[18]
    DIRECTION INPUT ;
    USE SIGNAL ;
    SHAPE ABUTMENT ;
    PORT
      LAYER M4 ;
      RECT 0.000 122.640 0.024 122.664 ;
    END
  END wd_in_A[18]
  PIN wd_in_B[18]
    DIRECTION INPUT ;
    USE SIGNAL ;
    SHAPE ABUTMENT ;
    PORT
      LAYER M4 ;
      RECT 46.906 122.640 46.930 122.664 ;
    END
  END wd_in_B[18]
  PIN wd_in_A[19]
    DIRECTION INPUT ;
    USE SIGNAL ;
    SHAPE ABUTMENT ;
    PORT
      LAYER M4 ;
      RECT 0.000 124.128 0.024 124.152 ;
    END
  END wd_in_A[19]
  PIN wd_in_B[19]
    DIRECTION INPUT ;
    USE SIGNAL ;
    SHAPE ABUTMENT ;
    PORT
      LAYER M4 ;
      RECT 46.906 124.128 46.930 124.152 ;
    END
  END wd_in_B[19]
  PIN wd_in_A[20]
    DIRECTION INPUT ;
    USE SIGNAL ;
    SHAPE ABUTMENT ;
    PORT
      LAYER M4 ;
      RECT 0.000 125.616 0.024 125.640 ;
    END
  END wd_in_A[20]
  PIN wd_in_B[20]
    DIRECTION INPUT ;
    USE SIGNAL ;
    SHAPE ABUTMENT ;
    PORT
      LAYER M4 ;
      RECT 46.906 125.616 46.930 125.640 ;
    END
  END wd_in_B[20]
  PIN wd_in_A[21]
    DIRECTION INPUT ;
    USE SIGNAL ;
    SHAPE ABUTMENT ;
    PORT
      LAYER M4 ;
      RECT 0.000 127.104 0.024 127.128 ;
    END
  END wd_in_A[21]
  PIN wd_in_B[21]
    DIRECTION INPUT ;
    USE SIGNAL ;
    SHAPE ABUTMENT ;
    PORT
      LAYER M4 ;
      RECT 46.906 127.104 46.930 127.128 ;
    END
  END wd_in_B[21]
  PIN wd_in_A[22]
    DIRECTION INPUT ;
    USE SIGNAL ;
    SHAPE ABUTMENT ;
    PORT
      LAYER M4 ;
      RECT 0.000 128.592 0.024 128.616 ;
    END
  END wd_in_A[22]
  PIN wd_in_B[22]
    DIRECTION INPUT ;
    USE SIGNAL ;
    SHAPE ABUTMENT ;
    PORT
      LAYER M4 ;
      RECT 46.906 128.592 46.930 128.616 ;
    END
  END wd_in_B[22]
  PIN wd_in_A[23]
    DIRECTION INPUT ;
    USE SIGNAL ;
    SHAPE ABUTMENT ;
    PORT
      LAYER M4 ;
      RECT 0.000 130.080 0.024 130.104 ;
    END
  END wd_in_A[23]
  PIN wd_in_B[23]
    DIRECTION INPUT ;
    USE SIGNAL ;
    SHAPE ABUTMENT ;
    PORT
      LAYER M4 ;
      RECT 46.906 130.080 46.930 130.104 ;
    END
  END wd_in_B[23]
  PIN wd_in_A[24]
    DIRECTION INPUT ;
    USE SIGNAL ;
    SHAPE ABUTMENT ;
    PORT
      LAYER M4 ;
      RECT 0.000 131.568 0.024 131.592 ;
    END
  END wd_in_A[24]
  PIN wd_in_B[24]
    DIRECTION INPUT ;
    USE SIGNAL ;
    SHAPE ABUTMENT ;
    PORT
      LAYER M4 ;
      RECT 46.906 131.568 46.930 131.592 ;
    END
  END wd_in_B[24]
  PIN wd_in_A[25]
    DIRECTION INPUT ;
    USE SIGNAL ;
    SHAPE ABUTMENT ;
    PORT
      LAYER M4 ;
      RECT 0.000 133.056 0.024 133.080 ;
    END
  END wd_in_A[25]
  PIN wd_in_B[25]
    DIRECTION INPUT ;
    USE SIGNAL ;
    SHAPE ABUTMENT ;
    PORT
      LAYER M4 ;
      RECT 46.906 133.056 46.930 133.080 ;
    END
  END wd_in_B[25]
  PIN wd_in_A[26]
    DIRECTION INPUT ;
    USE SIGNAL ;
    SHAPE ABUTMENT ;
    PORT
      LAYER M4 ;
      RECT 0.000 134.544 0.024 134.568 ;
    END
  END wd_in_A[26]
  PIN wd_in_B[26]
    DIRECTION INPUT ;
    USE SIGNAL ;
    SHAPE ABUTMENT ;
    PORT
      LAYER M4 ;
      RECT 46.906 134.544 46.930 134.568 ;
    END
  END wd_in_B[26]
  PIN wd_in_A[27]
    DIRECTION INPUT ;
    USE SIGNAL ;
    SHAPE ABUTMENT ;
    PORT
      LAYER M4 ;
      RECT 0.000 136.032 0.024 136.056 ;
    END
  END wd_in_A[27]
  PIN wd_in_B[27]
    DIRECTION INPUT ;
    USE SIGNAL ;
    SHAPE ABUTMENT ;
    PORT
      LAYER M4 ;
      RECT 46.906 136.032 46.930 136.056 ;
    END
  END wd_in_B[27]
  PIN wd_in_A[28]
    DIRECTION INPUT ;
    USE SIGNAL ;
    SHAPE ABUTMENT ;
    PORT
      LAYER M4 ;
      RECT 0.000 137.520 0.024 137.544 ;
    END
  END wd_in_A[28]
  PIN wd_in_B[28]
    DIRECTION INPUT ;
    USE SIGNAL ;
    SHAPE ABUTMENT ;
    PORT
      LAYER M4 ;
      RECT 46.906 137.520 46.930 137.544 ;
    END
  END wd_in_B[28]
  PIN wd_in_A[29]
    DIRECTION INPUT ;
    USE SIGNAL ;
    SHAPE ABUTMENT ;
    PORT
      LAYER M4 ;
      RECT 0.000 139.008 0.024 139.032 ;
    END
  END wd_in_A[29]
  PIN wd_in_B[29]
    DIRECTION INPUT ;
    USE SIGNAL ;
    SHAPE ABUTMENT ;
    PORT
      LAYER M4 ;
      RECT 46.906 139.008 46.930 139.032 ;
    END
  END wd_in_B[29]
  PIN wd_in_A[30]
    DIRECTION INPUT ;
    USE SIGNAL ;
    SHAPE ABUTMENT ;
    PORT
      LAYER M4 ;
      RECT 0.000 140.496 0.024 140.520 ;
    END
  END wd_in_A[30]
  PIN wd_in_B[30]
    DIRECTION INPUT ;
    USE SIGNAL ;
    SHAPE ABUTMENT ;
    PORT
      LAYER M4 ;
      RECT 46.906 140.496 46.930 140.520 ;
    END
  END wd_in_B[30]
  PIN wd_in_A[31]
    DIRECTION INPUT ;
    USE SIGNAL ;
    SHAPE ABUTMENT ;
    PORT
      LAYER M4 ;
      RECT 0.000 141.984 0.024 142.008 ;
    END
  END wd_in_A[31]
  PIN wd_in_B[31]
    DIRECTION INPUT ;
    USE SIGNAL ;
    SHAPE ABUTMENT ;
    PORT
      LAYER M4 ;
      RECT 46.906 141.984 46.930 142.008 ;
    END
  END wd_in_B[31]
  PIN addr_in_A[0]
    DIRECTION INPUT ;
    USE SIGNAL ;
    SHAPE ABUTMENT ;
    PORT
      LAYER M4 ;
      RECT 0.000 143.760 0.024 143.784 ;
    END
  END addr_in_A[0]
  PIN addr_in_B[0]
    DIRECTION INPUT ;
    USE SIGNAL ;
    SHAPE ABUTMENT ;
    PORT
      LAYER M4 ;
      RECT 46.906 143.760 46.930 143.784 ;
    END
  END addr_in_B[0]
  PIN addr_in_A[1]
    DIRECTION INPUT ;
    USE SIGNAL ;
    SHAPE ABUTMENT ;
    PORT
      LAYER M4 ;
      RECT 0.000 145.248 0.024 145.272 ;
    END
  END addr_in_A[1]
  PIN addr_in_B[1]
    DIRECTION INPUT ;
    USE SIGNAL ;
    SHAPE ABUTMENT ;
    PORT
      LAYER M4 ;
      RECT 46.906 145.248 46.930 145.272 ;
    END
  END addr_in_B[1]
  PIN addr_in_A[2]
    DIRECTION INPUT ;
    USE SIGNAL ;
    SHAPE ABUTMENT ;
    PORT
      LAYER M4 ;
      RECT 0.000 146.736 0.024 146.760 ;
    END
  END addr_in_A[2]
  PIN addr_in_B[2]
    DIRECTION INPUT ;
    USE SIGNAL ;
    SHAPE ABUTMENT ;
    PORT
      LAYER M4 ;
      RECT 46.906 146.736 46.930 146.760 ;
    END
  END addr_in_B[2]
  PIN addr_in_A[3]
    DIRECTION INPUT ;
    USE SIGNAL ;
    SHAPE ABUTMENT ;
    PORT
      LAYER M4 ;
      RECT 0.000 148.224 0.024 148.248 ;
    END
  END addr_in_A[3]
  PIN addr_in_B[3]
    DIRECTION INPUT ;
    USE SIGNAL ;
    SHAPE ABUTMENT ;
    PORT
      LAYER M4 ;
      RECT 46.906 148.224 46.930 148.248 ;
    END
  END addr_in_B[3]
  PIN addr_in_A[4]
    DIRECTION INPUT ;
    USE SIGNAL ;
    SHAPE ABUTMENT ;
    PORT
      LAYER M4 ;
      RECT 0.000 149.712 0.024 149.736 ;
    END
  END addr_in_A[4]
  PIN addr_in_B[4]
    DIRECTION INPUT ;
    USE SIGNAL ;
    SHAPE ABUTMENT ;
    PORT
      LAYER M4 ;
      RECT 46.906 149.712 46.930 149.736 ;
    END
  END addr_in_B[4]
  PIN addr_in_A[5]
    DIRECTION INPUT ;
    USE SIGNAL ;
    SHAPE ABUTMENT ;
    PORT
      LAYER M4 ;
      RECT 0.000 151.200 0.024 151.224 ;
    END
  END addr_in_A[5]
  PIN addr_in_B[5]
    DIRECTION INPUT ;
    USE SIGNAL ;
    SHAPE ABUTMENT ;
    PORT
      LAYER M4 ;
      RECT 46.906 151.200 46.930 151.224 ;
    END
  END addr_in_B[5]
  PIN addr_in_A[6]
    DIRECTION INPUT ;
    USE SIGNAL ;
    SHAPE ABUTMENT ;
    PORT
      LAYER M4 ;
      RECT 0.000 152.688 0.024 152.712 ;
    END
  END addr_in_A[6]
  PIN addr_in_B[6]
    DIRECTION INPUT ;
    USE SIGNAL ;
    SHAPE ABUTMENT ;
    PORT
      LAYER M4 ;
      RECT 46.906 152.688 46.930 152.712 ;
    END
  END addr_in_B[6]
  PIN addr_in_A[7]
    DIRECTION INPUT ;
    USE SIGNAL ;
    SHAPE ABUTMENT ;
    PORT
      LAYER M4 ;
      RECT 0.000 154.176 0.024 154.200 ;
    END
  END addr_in_A[7]
  PIN addr_in_B[7]
    DIRECTION INPUT ;
    USE SIGNAL ;
    SHAPE ABUTMENT ;
    PORT
      LAYER M4 ;
      RECT 46.906 154.176 46.930 154.200 ;
    END
  END addr_in_B[7]
  PIN addr_in_A[8]
    DIRECTION INPUT ;
    USE SIGNAL ;
    SHAPE ABUTMENT ;
    PORT
      LAYER M4 ;
      RECT 0.000 155.664 0.024 155.688 ;
    END
  END addr_in_A[8]
  PIN addr_in_B[8]
    DIRECTION INPUT ;
    USE SIGNAL ;
    SHAPE ABUTMENT ;
    PORT
      LAYER M4 ;
      RECT 46.906 155.664 46.930 155.688 ;
    END
  END addr_in_B[8]
  PIN addr_in_A[9]
    DIRECTION INPUT ;
    USE SIGNAL ;
    SHAPE ABUTMENT ;
    PORT
      LAYER M4 ;
      RECT 0.000 157.152 0.024 157.176 ;
    END
  END addr_in_A[9]
  PIN addr_in_B[9]
    DIRECTION INPUT ;
    USE SIGNAL ;
    SHAPE ABUTMENT ;
    PORT
      LAYER M4 ;
      RECT 46.906 157.152 46.930 157.176 ;
    END
  END addr_in_B[9]
  PIN addr_in_A[10]
    DIRECTION INPUT ;
    USE SIGNAL ;
    SHAPE ABUTMENT ;
    PORT
      LAYER M4 ;
      RECT 0.000 158.640 0.024 158.664 ;
    END
  END addr_in_A[10]
  PIN addr_in_B[10]
    DIRECTION INPUT ;
    USE SIGNAL ;
    SHAPE ABUTMENT ;
    PORT
      LAYER M4 ;
      RECT 46.906 158.640 46.930 158.664 ;
    END
  END addr_in_B[10]
  PIN addr_in_A[11]
    DIRECTION INPUT ;
    USE SIGNAL ;
    SHAPE ABUTMENT ;
    PORT
      LAYER M4 ;
      RECT 0.000 160.128 0.024 160.152 ;
    END
  END addr_in_A[11]
  PIN addr_in_B[11]
    DIRECTION INPUT ;
    USE SIGNAL ;
    SHAPE ABUTMENT ;
    PORT
      LAYER M4 ;
      RECT 46.906 160.128 46.930 160.152 ;
    END
  END addr_in_B[11]
  PIN we_in_A
    DIRECTION INPUT ;
    USE SIGNAL ;
    SHAPE ABUTMENT ;
    PORT
      LAYER M4 ;
      RECT 0.000 161.904 0.024 161.928 ;
    END
  END we_in_A
  PIN we_in_B
    DIRECTION INPUT ;
    USE SIGNAL ;
    SHAPE ABUTMENT ;
    PORT
      LAYER M4 ;
      RECT 46.906 161.904 46.930 161.928 ;
    END
  END we_in_B
  PIN ce_in
    DIRECTION INPUT ;
    USE SIGNAL ;
    SHAPE ABUTMENT ;
    PORT
      LAYER M4 ;
      RECT 0.000 163.392 0.024 163.416 ;
    END
  END ce_in
  PIN clk
    DIRECTION INPUT ;
    USE SIGNAL ;
    SHAPE ABUTMENT ;
    PORT
      LAYER M4 ;
      RECT 0.000 164.880 0.024 164.904 ;
    END
  END clk
  PIN VSS
    DIRECTION INOUT ;
    USE GROUND ;
    PORT
      LAYER M4 ;
      RECT 0.048 0.000 46.882 0.096 ;
      RECT 0.048 0.768 46.882 0.864 ;
      RECT 0.048 1.536 46.882 1.632 ;
      RECT 0.048 2.304 46.882 2.400 ;
      RECT 0.048 3.072 46.882 3.168 ;
      RECT 0.048 3.840 46.882 3.936 ;
      RECT 0.048 4.608 46.882 4.704 ;
      RECT 0.048 5.376 46.882 5.472 ;
      RECT 0.048 6.144 46.882 6.240 ;
      RECT 0.048 6.912 46.882 7.008 ;
      RECT 0.048 7.680 46.882 7.776 ;
      RECT 0.048 8.448 46.882 8.544 ;
      RECT 0.048 9.216 46.882 9.312 ;
      RECT 0.048 9.984 46.882 10.080 ;
      RECT 0.048 10.752 46.882 10.848 ;
      RECT 0.048 11.520 46.882 11.616 ;
      RECT 0.048 12.288 46.882 12.384 ;
      RECT 0.048 13.056 46.882 13.152 ;
      RECT 0.048 13.824 46.882 13.920 ;
      RECT 0.048 14.592 46.882 14.688 ;
      RECT 0.048 15.360 46.882 15.456 ;
      RECT 0.048 16.128 46.882 16.224 ;
      RECT 0.048 16.896 46.882 16.992 ;
      RECT 0.048 17.664 46.882 17.760 ;
      RECT 0.048 18.432 46.882 18.528 ;
      RECT 0.048 19.200 46.882 19.296 ;
      RECT 0.048 19.968 46.882 20.064 ;
      RECT 0.048 20.736 46.882 20.832 ;
      RECT 0.048 21.504 46.882 21.600 ;
      RECT 0.048 22.272 46.882 22.368 ;
      RECT 0.048 23.040 46.882 23.136 ;
      RECT 0.048 23.808 46.882 23.904 ;
      RECT 0.048 24.576 46.882 24.672 ;
      RECT 0.048 25.344 46.882 25.440 ;
      RECT 0.048 26.112 46.882 26.208 ;
      RECT 0.048 26.880 46.882 26.976 ;
      RECT 0.048 27.648 46.882 27.744 ;
      RECT 0.048 28.416 46.882 28.512 ;
      RECT 0.048 29.184 46.882 29.280 ;
      RECT 0.048 29.952 46.882 30.048 ;
      RECT 0.048 30.720 46.882 30.816 ;
      RECT 0.048 31.488 46.882 31.584 ;
      RECT 0.048 32.256 46.882 32.352 ;
      RECT 0.048 33.024 46.882 33.120 ;
      RECT 0.048 33.792 46.882 33.888 ;
      RECT 0.048 34.560 46.882 34.656 ;
      RECT 0.048 35.328 46.882 35.424 ;
      RECT 0.048 36.096 46.882 36.192 ;
      RECT 0.048 36.864 46.882 36.960 ;
      RECT 0.048 37.632 46.882 37.728 ;
      RECT 0.048 38.400 46.882 38.496 ;
      RECT 0.048 39.168 46.882 39.264 ;
      RECT 0.048 39.936 46.882 40.032 ;
      RECT 0.048 40.704 46.882 40.800 ;
      RECT 0.048 41.472 46.882 41.568 ;
      RECT 0.048 42.240 46.882 42.336 ;
      RECT 0.048 43.008 46.882 43.104 ;
      RECT 0.048 43.776 46.882 43.872 ;
      RECT 0.048 44.544 46.882 44.640 ;
      RECT 0.048 45.312 46.882 45.408 ;
      RECT 0.048 46.080 46.882 46.176 ;
      RECT 0.048 46.848 46.882 46.944 ;
      RECT 0.048 47.616 46.882 47.712 ;
      RECT 0.048 48.384 46.882 48.480 ;
      RECT 0.048 49.152 46.882 49.248 ;
      RECT 0.048 49.920 46.882 50.016 ;
      RECT 0.048 50.688 46.882 50.784 ;
      RECT 0.048 51.456 46.882 51.552 ;
      RECT 0.048 52.224 46.882 52.320 ;
      RECT 0.048 52.992 46.882 53.088 ;
      RECT 0.048 53.760 46.882 53.856 ;
      RECT 0.048 54.528 46.882 54.624 ;
      RECT 0.048 55.296 46.882 55.392 ;
      RECT 0.048 56.064 46.882 56.160 ;
      RECT 0.048 56.832 46.882 56.928 ;
      RECT 0.048 57.600 46.882 57.696 ;
      RECT 0.048 58.368 46.882 58.464 ;
      RECT 0.048 59.136 46.882 59.232 ;
      RECT 0.048 59.904 46.882 60.000 ;
      RECT 0.048 60.672 46.882 60.768 ;
      RECT 0.048 61.440 46.882 61.536 ;
      RECT 0.048 62.208 46.882 62.304 ;
      RECT 0.048 62.976 46.882 63.072 ;
      RECT 0.048 63.744 46.882 63.840 ;
      RECT 0.048 64.512 46.882 64.608 ;
      RECT 0.048 65.280 46.882 65.376 ;
      RECT 0.048 66.048 46.882 66.144 ;
      RECT 0.048 66.816 46.882 66.912 ;
      RECT 0.048 67.584 46.882 67.680 ;
      RECT 0.048 68.352 46.882 68.448 ;
      RECT 0.048 69.120 46.882 69.216 ;
      RECT 0.048 69.888 46.882 69.984 ;
      RECT 0.048 70.656 46.882 70.752 ;
      RECT 0.048 71.424 46.882 71.520 ;
      RECT 0.048 72.192 46.882 72.288 ;
      RECT 0.048 72.960 46.882 73.056 ;
      RECT 0.048 73.728 46.882 73.824 ;
      RECT 0.048 74.496 46.882 74.592 ;
      RECT 0.048 75.264 46.882 75.360 ;
      RECT 0.048 76.032 46.882 76.128 ;
      RECT 0.048 76.800 46.882 76.896 ;
      RECT 0.048 77.568 46.882 77.664 ;
      RECT 0.048 78.336 46.882 78.432 ;
      RECT 0.048 79.104 46.882 79.200 ;
      RECT 0.048 79.872 46.882 79.968 ;
      RECT 0.048 80.640 46.882 80.736 ;
      RECT 0.048 81.408 46.882 81.504 ;
      RECT 0.048 82.176 46.882 82.272 ;
      RECT 0.048 82.944 46.882 83.040 ;
      RECT 0.048 83.712 46.882 83.808 ;
      RECT 0.048 84.480 46.882 84.576 ;
      RECT 0.048 85.248 46.882 85.344 ;
      RECT 0.048 86.016 46.882 86.112 ;
      RECT 0.048 86.784 46.882 86.880 ;
      RECT 0.048 87.552 46.882 87.648 ;
      RECT 0.048 88.320 46.882 88.416 ;
      RECT 0.048 89.088 46.882 89.184 ;
      RECT 0.048 89.856 46.882 89.952 ;
      RECT 0.048 90.624 46.882 90.720 ;
      RECT 0.048 91.392 46.882 91.488 ;
      RECT 0.048 92.160 46.882 92.256 ;
      RECT 0.048 92.928 46.882 93.024 ;
      RECT 0.048 93.696 46.882 93.792 ;
      RECT 0.048 94.464 46.882 94.560 ;
      RECT 0.048 95.232 46.882 95.328 ;
      RECT 0.048 96.000 46.882 96.096 ;
      RECT 0.048 96.768 46.882 96.864 ;
      RECT 0.048 97.536 46.882 97.632 ;
      RECT 0.048 98.304 46.882 98.400 ;
      RECT 0.048 99.072 46.882 99.168 ;
      RECT 0.048 99.840 46.882 99.936 ;
      RECT 0.048 100.608 46.882 100.704 ;
      RECT 0.048 101.376 46.882 101.472 ;
      RECT 0.048 102.144 46.882 102.240 ;
      RECT 0.048 102.912 46.882 103.008 ;
      RECT 0.048 103.680 46.882 103.776 ;
      RECT 0.048 104.448 46.882 104.544 ;
      RECT 0.048 105.216 46.882 105.312 ;
      RECT 0.048 105.984 46.882 106.080 ;
      RECT 0.048 106.752 46.882 106.848 ;
      RECT 0.048 107.520 46.882 107.616 ;
      RECT 0.048 108.288 46.882 108.384 ;
      RECT 0.048 109.056 46.882 109.152 ;
      RECT 0.048 109.824 46.882 109.920 ;
      RECT 0.048 110.592 46.882 110.688 ;
      RECT 0.048 111.360 46.882 111.456 ;
      RECT 0.048 112.128 46.882 112.224 ;
      RECT 0.048 112.896 46.882 112.992 ;
      RECT 0.048 113.664 46.882 113.760 ;
      RECT 0.048 114.432 46.882 114.528 ;
      RECT 0.048 115.200 46.882 115.296 ;
      RECT 0.048 115.968 46.882 116.064 ;
      RECT 0.048 116.736 46.882 116.832 ;
      RECT 0.048 117.504 46.882 117.600 ;
      RECT 0.048 118.272 46.882 118.368 ;
      RECT 0.048 119.040 46.882 119.136 ;
      RECT 0.048 119.808 46.882 119.904 ;
      RECT 0.048 120.576 46.882 120.672 ;
      RECT 0.048 121.344 46.882 121.440 ;
      RECT 0.048 122.112 46.882 122.208 ;
      RECT 0.048 122.880 46.882 122.976 ;
      RECT 0.048 123.648 46.882 123.744 ;
      RECT 0.048 124.416 46.882 124.512 ;
      RECT 0.048 125.184 46.882 125.280 ;
      RECT 0.048 125.952 46.882 126.048 ;
      RECT 0.048 126.720 46.882 126.816 ;
      RECT 0.048 127.488 46.882 127.584 ;
      RECT 0.048 128.256 46.882 128.352 ;
      RECT 0.048 129.024 46.882 129.120 ;
      RECT 0.048 129.792 46.882 129.888 ;
      RECT 0.048 130.560 46.882 130.656 ;
      RECT 0.048 131.328 46.882 131.424 ;
      RECT 0.048 132.096 46.882 132.192 ;
      RECT 0.048 132.864 46.882 132.960 ;
      RECT 0.048 133.632 46.882 133.728 ;
      RECT 0.048 134.400 46.882 134.496 ;
      RECT 0.048 135.168 46.882 135.264 ;
      RECT 0.048 135.936 46.882 136.032 ;
      RECT 0.048 136.704 46.882 136.800 ;
      RECT 0.048 137.472 46.882 137.568 ;
      RECT 0.048 138.240 46.882 138.336 ;
      RECT 0.048 139.008 46.882 139.104 ;
      RECT 0.048 139.776 46.882 139.872 ;
      RECT 0.048 140.544 46.882 140.640 ;
      RECT 0.048 141.312 46.882 141.408 ;
      RECT 0.048 142.080 46.882 142.176 ;
      RECT 0.048 142.848 46.882 142.944 ;
      RECT 0.048 143.616 46.882 143.712 ;
      RECT 0.048 144.384 46.882 144.480 ;
      RECT 0.048 145.152 46.882 145.248 ;
      RECT 0.048 145.920 46.882 146.016 ;
      RECT 0.048 146.688 46.882 146.784 ;
      RECT 0.048 147.456 46.882 147.552 ;
      RECT 0.048 148.224 46.882 148.320 ;
      RECT 0.048 148.992 46.882 149.088 ;
      RECT 0.048 149.760 46.882 149.856 ;
      RECT 0.048 150.528 46.882 150.624 ;
      RECT 0.048 151.296 46.882 151.392 ;
      RECT 0.048 152.064 46.882 152.160 ;
      RECT 0.048 152.832 46.882 152.928 ;
      RECT 0.048 153.600 46.882 153.696 ;
      RECT 0.048 154.368 46.882 154.464 ;
      RECT 0.048 155.136 46.882 155.232 ;
      RECT 0.048 155.904 46.882 156.000 ;
      RECT 0.048 156.672 46.882 156.768 ;
      RECT 0.048 157.440 46.882 157.536 ;
      RECT 0.048 158.208 46.882 158.304 ;
      RECT 0.048 158.976 46.882 159.072 ;
      RECT 0.048 159.744 46.882 159.840 ;
      RECT 0.048 160.512 46.882 160.608 ;
      RECT 0.048 161.280 46.882 161.376 ;
      RECT 0.048 162.048 46.882 162.144 ;
      RECT 0.048 162.816 46.882 162.912 ;
      RECT 0.048 163.584 46.882 163.680 ;
      RECT 0.048 164.352 46.882 164.448 ;
      RECT 0.048 165.120 46.882 165.216 ;
      RECT 0.048 165.888 46.882 165.984 ;
    END
  END VSS
  PIN VDD
    DIRECTION INOUT ;
    USE POWER ;
    PORT
      LAYER M4 ;
      RECT 0.048 0.384 46.882 0.480 ;
      RECT 0.048 1.152 46.882 1.248 ;
      RECT 0.048 1.920 46.882 2.016 ;
      RECT 0.048 2.688 46.882 2.784 ;
      RECT 0.048 3.456 46.882 3.552 ;
      RECT 0.048 4.224 46.882 4.320 ;
      RECT 0.048 4.992 46.882 5.088 ;
      RECT 0.048 5.760 46.882 5.856 ;
      RECT 0.048 6.528 46.882 6.624 ;
      RECT 0.048 7.296 46.882 7.392 ;
      RECT 0.048 8.064 46.882 8.160 ;
      RECT 0.048 8.832 46.882 8.928 ;
      RECT 0.048 9.600 46.882 9.696 ;
      RECT 0.048 10.368 46.882 10.464 ;
      RECT 0.048 11.136 46.882 11.232 ;
      RECT 0.048 11.904 46.882 12.000 ;
      RECT 0.048 12.672 46.882 12.768 ;
      RECT 0.048 13.440 46.882 13.536 ;
      RECT 0.048 14.208 46.882 14.304 ;
      RECT 0.048 14.976 46.882 15.072 ;
      RECT 0.048 15.744 46.882 15.840 ;
      RECT 0.048 16.512 46.882 16.608 ;
      RECT 0.048 17.280 46.882 17.376 ;
      RECT 0.048 18.048 46.882 18.144 ;
      RECT 0.048 18.816 46.882 18.912 ;
      RECT 0.048 19.584 46.882 19.680 ;
      RECT 0.048 20.352 46.882 20.448 ;
      RECT 0.048 21.120 46.882 21.216 ;
      RECT 0.048 21.888 46.882 21.984 ;
      RECT 0.048 22.656 46.882 22.752 ;
      RECT 0.048 23.424 46.882 23.520 ;
      RECT 0.048 24.192 46.882 24.288 ;
      RECT 0.048 24.960 46.882 25.056 ;
      RECT 0.048 25.728 46.882 25.824 ;
      RECT 0.048 26.496 46.882 26.592 ;
      RECT 0.048 27.264 46.882 27.360 ;
      RECT 0.048 28.032 46.882 28.128 ;
      RECT 0.048 28.800 46.882 28.896 ;
      RECT 0.048 29.568 46.882 29.664 ;
      RECT 0.048 30.336 46.882 30.432 ;
      RECT 0.048 31.104 46.882 31.200 ;
      RECT 0.048 31.872 46.882 31.968 ;
      RECT 0.048 32.640 46.882 32.736 ;
      RECT 0.048 33.408 46.882 33.504 ;
      RECT 0.048 34.176 46.882 34.272 ;
      RECT 0.048 34.944 46.882 35.040 ;
      RECT 0.048 35.712 46.882 35.808 ;
      RECT 0.048 36.480 46.882 36.576 ;
      RECT 0.048 37.248 46.882 37.344 ;
      RECT 0.048 38.016 46.882 38.112 ;
      RECT 0.048 38.784 46.882 38.880 ;
      RECT 0.048 39.552 46.882 39.648 ;
      RECT 0.048 40.320 46.882 40.416 ;
      RECT 0.048 41.088 46.882 41.184 ;
      RECT 0.048 41.856 46.882 41.952 ;
      RECT 0.048 42.624 46.882 42.720 ;
      RECT 0.048 43.392 46.882 43.488 ;
      RECT 0.048 44.160 46.882 44.256 ;
      RECT 0.048 44.928 46.882 45.024 ;
      RECT 0.048 45.696 46.882 45.792 ;
      RECT 0.048 46.464 46.882 46.560 ;
      RECT 0.048 47.232 46.882 47.328 ;
      RECT 0.048 48.000 46.882 48.096 ;
      RECT 0.048 48.768 46.882 48.864 ;
      RECT 0.048 49.536 46.882 49.632 ;
      RECT 0.048 50.304 46.882 50.400 ;
      RECT 0.048 51.072 46.882 51.168 ;
      RECT 0.048 51.840 46.882 51.936 ;
      RECT 0.048 52.608 46.882 52.704 ;
      RECT 0.048 53.376 46.882 53.472 ;
      RECT 0.048 54.144 46.882 54.240 ;
      RECT 0.048 54.912 46.882 55.008 ;
      RECT 0.048 55.680 46.882 55.776 ;
      RECT 0.048 56.448 46.882 56.544 ;
      RECT 0.048 57.216 46.882 57.312 ;
      RECT 0.048 57.984 46.882 58.080 ;
      RECT 0.048 58.752 46.882 58.848 ;
      RECT 0.048 59.520 46.882 59.616 ;
      RECT 0.048 60.288 46.882 60.384 ;
      RECT 0.048 61.056 46.882 61.152 ;
      RECT 0.048 61.824 46.882 61.920 ;
      RECT 0.048 62.592 46.882 62.688 ;
      RECT 0.048 63.360 46.882 63.456 ;
      RECT 0.048 64.128 46.882 64.224 ;
      RECT 0.048 64.896 46.882 64.992 ;
      RECT 0.048 65.664 46.882 65.760 ;
      RECT 0.048 66.432 46.882 66.528 ;
      RECT 0.048 67.200 46.882 67.296 ;
      RECT 0.048 67.968 46.882 68.064 ;
      RECT 0.048 68.736 46.882 68.832 ;
      RECT 0.048 69.504 46.882 69.600 ;
      RECT 0.048 70.272 46.882 70.368 ;
      RECT 0.048 71.040 46.882 71.136 ;
      RECT 0.048 71.808 46.882 71.904 ;
      RECT 0.048 72.576 46.882 72.672 ;
      RECT 0.048 73.344 46.882 73.440 ;
      RECT 0.048 74.112 46.882 74.208 ;
      RECT 0.048 74.880 46.882 74.976 ;
      RECT 0.048 75.648 46.882 75.744 ;
      RECT 0.048 76.416 46.882 76.512 ;
      RECT 0.048 77.184 46.882 77.280 ;
      RECT 0.048 77.952 46.882 78.048 ;
      RECT 0.048 78.720 46.882 78.816 ;
      RECT 0.048 79.488 46.882 79.584 ;
      RECT 0.048 80.256 46.882 80.352 ;
      RECT 0.048 81.024 46.882 81.120 ;
      RECT 0.048 81.792 46.882 81.888 ;
      RECT 0.048 82.560 46.882 82.656 ;
      RECT 0.048 83.328 46.882 83.424 ;
      RECT 0.048 84.096 46.882 84.192 ;
      RECT 0.048 84.864 46.882 84.960 ;
      RECT 0.048 85.632 46.882 85.728 ;
      RECT 0.048 86.400 46.882 86.496 ;
      RECT 0.048 87.168 46.882 87.264 ;
      RECT 0.048 87.936 46.882 88.032 ;
      RECT 0.048 88.704 46.882 88.800 ;
      RECT 0.048 89.472 46.882 89.568 ;
      RECT 0.048 90.240 46.882 90.336 ;
      RECT 0.048 91.008 46.882 91.104 ;
      RECT 0.048 91.776 46.882 91.872 ;
      RECT 0.048 92.544 46.882 92.640 ;
      RECT 0.048 93.312 46.882 93.408 ;
      RECT 0.048 94.080 46.882 94.176 ;
      RECT 0.048 94.848 46.882 94.944 ;
      RECT 0.048 95.616 46.882 95.712 ;
      RECT 0.048 96.384 46.882 96.480 ;
      RECT 0.048 97.152 46.882 97.248 ;
      RECT 0.048 97.920 46.882 98.016 ;
      RECT 0.048 98.688 46.882 98.784 ;
      RECT 0.048 99.456 46.882 99.552 ;
      RECT 0.048 100.224 46.882 100.320 ;
      RECT 0.048 100.992 46.882 101.088 ;
      RECT 0.048 101.760 46.882 101.856 ;
      RECT 0.048 102.528 46.882 102.624 ;
      RECT 0.048 103.296 46.882 103.392 ;
      RECT 0.048 104.064 46.882 104.160 ;
      RECT 0.048 104.832 46.882 104.928 ;
      RECT 0.048 105.600 46.882 105.696 ;
      RECT 0.048 106.368 46.882 106.464 ;
      RECT 0.048 107.136 46.882 107.232 ;
      RECT 0.048 107.904 46.882 108.000 ;
      RECT 0.048 108.672 46.882 108.768 ;
      RECT 0.048 109.440 46.882 109.536 ;
      RECT 0.048 110.208 46.882 110.304 ;
      RECT 0.048 110.976 46.882 111.072 ;
      RECT 0.048 111.744 46.882 111.840 ;
      RECT 0.048 112.512 46.882 112.608 ;
      RECT 0.048 113.280 46.882 113.376 ;
      RECT 0.048 114.048 46.882 114.144 ;
      RECT 0.048 114.816 46.882 114.912 ;
      RECT 0.048 115.584 46.882 115.680 ;
      RECT 0.048 116.352 46.882 116.448 ;
      RECT 0.048 117.120 46.882 117.216 ;
      RECT 0.048 117.888 46.882 117.984 ;
      RECT 0.048 118.656 46.882 118.752 ;
      RECT 0.048 119.424 46.882 119.520 ;
      RECT 0.048 120.192 46.882 120.288 ;
      RECT 0.048 120.960 46.882 121.056 ;
      RECT 0.048 121.728 46.882 121.824 ;
      RECT 0.048 122.496 46.882 122.592 ;
      RECT 0.048 123.264 46.882 123.360 ;
      RECT 0.048 124.032 46.882 124.128 ;
      RECT 0.048 124.800 46.882 124.896 ;
      RECT 0.048 125.568 46.882 125.664 ;
      RECT 0.048 126.336 46.882 126.432 ;
      RECT 0.048 127.104 46.882 127.200 ;
      RECT 0.048 127.872 46.882 127.968 ;
      RECT 0.048 128.640 46.882 128.736 ;
      RECT 0.048 129.408 46.882 129.504 ;
      RECT 0.048 130.176 46.882 130.272 ;
      RECT 0.048 130.944 46.882 131.040 ;
      RECT 0.048 131.712 46.882 131.808 ;
      RECT 0.048 132.480 46.882 132.576 ;
      RECT 0.048 133.248 46.882 133.344 ;
      RECT 0.048 134.016 46.882 134.112 ;
      RECT 0.048 134.784 46.882 134.880 ;
      RECT 0.048 135.552 46.882 135.648 ;
      RECT 0.048 136.320 46.882 136.416 ;
      RECT 0.048 137.088 46.882 137.184 ;
      RECT 0.048 137.856 46.882 137.952 ;
      RECT 0.048 138.624 46.882 138.720 ;
      RECT 0.048 139.392 46.882 139.488 ;
      RECT 0.048 140.160 46.882 140.256 ;
      RECT 0.048 140.928 46.882 141.024 ;
      RECT 0.048 141.696 46.882 141.792 ;
      RECT 0.048 142.464 46.882 142.560 ;
      RECT 0.048 143.232 46.882 143.328 ;
      RECT 0.048 144.000 46.882 144.096 ;
      RECT 0.048 144.768 46.882 144.864 ;
      RECT 0.048 145.536 46.882 145.632 ;
      RECT 0.048 146.304 46.882 146.400 ;
      RECT 0.048 147.072 46.882 147.168 ;
      RECT 0.048 147.840 46.882 147.936 ;
      RECT 0.048 148.608 46.882 148.704 ;
      RECT 0.048 149.376 46.882 149.472 ;
      RECT 0.048 150.144 46.882 150.240 ;
      RECT 0.048 150.912 46.882 151.008 ;
      RECT 0.048 151.680 46.882 151.776 ;
      RECT 0.048 152.448 46.882 152.544 ;
      RECT 0.048 153.216 46.882 153.312 ;
      RECT 0.048 153.984 46.882 154.080 ;
      RECT 0.048 154.752 46.882 154.848 ;
      RECT 0.048 155.520 46.882 155.616 ;
      RECT 0.048 156.288 46.882 156.384 ;
      RECT 0.048 157.056 46.882 157.152 ;
      RECT 0.048 157.824 46.882 157.920 ;
      RECT 0.048 158.592 46.882 158.688 ;
      RECT 0.048 159.360 46.882 159.456 ;
      RECT 0.048 160.128 46.882 160.224 ;
      RECT 0.048 160.896 46.882 160.992 ;
      RECT 0.048 161.664 46.882 161.760 ;
      RECT 0.048 162.432 46.882 162.528 ;
      RECT 0.048 163.200 46.882 163.296 ;
      RECT 0.048 163.968 46.882 164.064 ;
      RECT 0.048 164.736 46.882 164.832 ;
      RECT 0.048 165.504 46.882 165.600 ;
      RECT 0.048 166.272 46.882 166.368 ;
    END
  END VDD
  OBS
    LAYER M1 ;
    RECT 0 0 46.930 166.600 ;
    LAYER M2 ;
    RECT 0 0 46.930 166.600 ;
    LAYER M3 ;
    RECT 0 0 46.930 166.600 ;
    LAYER M4 ;
    RECT 0 0 46.930 166.600 ;
  END
END fakeram7_dp_4096x32

END LIBRARY
